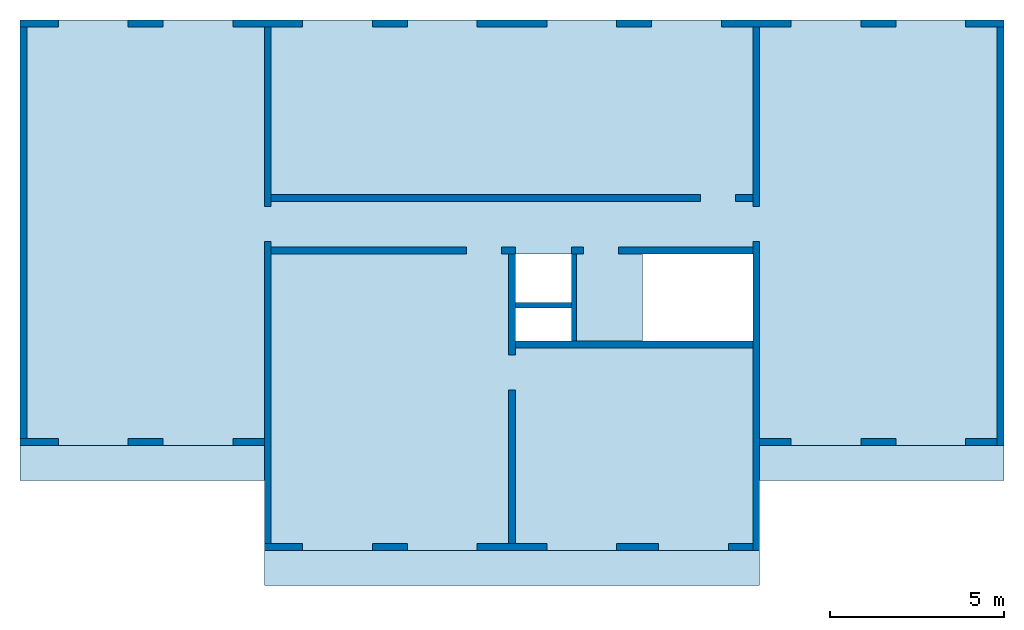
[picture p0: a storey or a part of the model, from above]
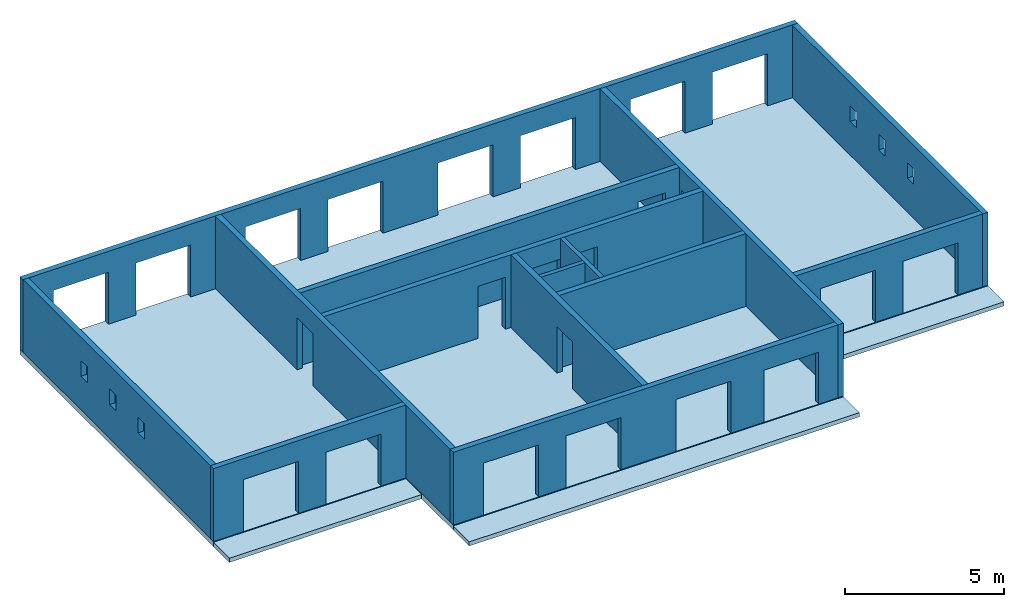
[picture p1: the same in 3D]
Properties of the parts of a building model (IFC2X3)

# File
Description: ViewDefinition [CoordinationView_V2.0, QuantityTakeOffAddOnView]
File name: Numéro de projet
Time: 2019-03-26T11:01:44
Written by: The EXPRESS Data Manager Version 5.02.0100.07 : 28 Aug 2013
Made in: 20180328_1600(x64) - Exporter 19.0.1.1 - Interface utilisateur alternative 19.0.1.1
Comment: STEP Physical File produced by: The EXPRESS Data Manager Version 5.02.0100.07 : 28 Aug 2013 * Module: EDMstepFileFactory/EDMstandAlone * Creation date: Tue Mar 26 11:01:44 2019 * Host: OCULUS-DGC * Database: C:\Users\TECHNI~1\AppData\Local\Temp\{C029B240-C833-49DC-BA55-EF145CA80EA0}\ifc * Database version: 5507 * Database creation date: Tue Mar 26 11:01:41 2019 * Schema: IFC2X3 * Model: DataRepository.ifc * Model creation date: Tue Mar 26 11:01:41 2019 * Header model: DataRepository.ifc_HeaderModel * Header model creation date: Tue Mar 26 11:01:41 2019 * EDMuser: sdai-user * EDMgroup: sdai-group * License ID and type: 5605 : Permanent license. Expiry date: * EDMstepFileFactory options: 020000

# IfcProject, Numéro de projet
LongName: Nom du projet; Phase: Etat du projet

# IfcSite, Default
RefLatitude: 48, 51, 57, 604064; RefLongitude: 2, 19, 58, 799800; RefElevation: 0 m

# IfcBuilding
Pset_BuildingCommon - NumberOfStoreys: 9

# IfcBuildingStorey (9)
Name | LongName | Elevation (m)
Fondations | Fondations | -3.3
R-1 | R-1 | -3
Rez de Chaussée | Rez de Chaussée | 0
R+1 | R+1 | 3
R+2 | R+2 | 6
R+3 | R+3 | 9
R+4 | R+4 | 12
R+5 | R+5 | 15
R+6 | R+6 | 18

# IfcFooting: Semelle filante:Soubassement de soutènement - 300 x 600 x 300 (8)
In: Fondations
PredefinedType: STRIP_FOOTING
Name (Semelle filante:Soubassement de soutènement - 300 x 600 x 300:...)
463532
463540
463560
463574
463588
463598
463612
463626

# IfcMember: Limon à la française:Limon à la française - 50 mm de largeur (60)
Type - PredefinedType: STRINGER
Pset_MemberCommon - LoadBearing: yes; IsExternal: no; Reference: Contremarche 190 mm max marche 250 mm
BaseQuantities - NetSurfaceArea: 35.8411 m2; NetVolume: 0.668562 m3
Name (Escalier assemblé:Escalier:...) | In | Span (m) = Length (m) | Slope (deg) | CrossSectionArea (m2) | OuterSurfaceArea (m2) | GrossSurfaceArea (m2) | GrossVolume (m3)
467169 Stringer 1 | Rez de Chaussée | 0.05 | 0 | 0.899041 | 0.270884 | 2.06897 | 0.044952
467169 Stringer 2 | Rez de Chaussée | 0.05 | 0 | 0.899041 | 0.270884 | 2.06897 | 0.044952
467169 Stringer 3 | Rez de Chaussée | 0.05 | 0 | 0.97861 | 0.290776 | 2.248 | 0.0489305
467169 Stringer 4 | Rez de Chaussée | 0.05 | 0 | 0.97861 | 0.290776 | 2.248 | 0.0489305
467169 Stringer 5 | Rez de Chaussée
467169 Stringer 6 | Rez de Chaussée | 0.4 | 0 | 0.115 | 1.89657 | 2.12657 | 0.046
467169 Stringer 7 | Rez de Chaussée
467169 Stringer 8 | Rez de Chaussée
467169 Stringer 9 | Rez de Chaussée | 0.4 | 0 | 0.01 | 0.216569 | 0.236569 | 0.004
467169 Stringer 10 | Rez de Chaussée
468124 Stringer 1 | R+2 | 0.05 | 0 | 0.899041 | 0.270884 | 2.06897 | 0.044952
468124 Stringer 2 | R+2 | 0.05 | 0 | 0.899041 | 0.270884 | 2.06897 | 0.044952
468124 Stringer 3 | R+2 | 0.05 | 0 | 0.97861 | 0.290776 | 2.248 | 0.0489305
468124 Stringer 4 | R+2 | 0.05 | 0 | 0.97861 | 0.290776 | 2.248 | 0.0489305
468124 Stringer 5 | R+2
468124 Stringer 6 | R+2 | 0.4 | 0 | 0.115 | 1.89657 | 2.12657 | 0.046
468124 Stringer 7 | R+2
468124 Stringer 8 | R+2
468124 Stringer 9 | R+2 | 0.4 | 0 | 0.01 | 0.216569 | 0.236569 | 0.004
468124 Stringer 10 | R+2
468213 Stringer 1 | R+3 | 0.05 | 0 | 0.899041 | 0.270884 | 2.06897 | 0.044952
468213 Stringer 2 | R+3 | 0.05 | 0 | 0.899041 | 0.270884 | 2.06897 | 0.044952
468213 Stringer 3 | R+3 | 0.05 | 0 | 0.97861 | 0.290776 | 2.248 | 0.0489305
468213 Stringer 4 | R+3 | 0.05 | 0 | 0.97861 | 0.290776 | 2.248 | 0.0489305
468213 Stringer 5 | R+3
468213 Stringer 6 | R+3 | 0.4 | 0 | 0.115 | 1.89657 | 2.12657 | 0.046
468213 Stringer 7 | R+3
468213 Stringer 8 | R+3
468213 Stringer 9 | R+3 | 0.4 | 0 | 0.01 | 0.216569 | 0.236569 | 0.004
468213 Stringer 10 | R+3
468302 Stringer 1 | R+4 | 0.05 | 0 | 0.899041 | 0.270884 | 2.06897 | 0.044952
468302 Stringer 2 | R+4 | 0.05 | 0 | 0.899041 | 0.270884 | 2.06897 | 0.044952
468302 Stringer 3 | R+4 | 0.05 | 0 | 0.97861 | 0.290776 | 2.248 | 0.0489305
468302 Stringer 4 | R+4 | 0.05 | 0 | 0.97861 | 0.290776 | 2.248 | 0.0489305
468302 Stringer 5 | R+4
468302 Stringer 6 | R+4 | 0.4 | 0 | 0.115 | 1.89657 | 2.12657 | 0.046
468302 Stringer 7 | R+4
468302 Stringer 8 | R+4
468302 Stringer 9 | R+4 | 0.4 | 0 | 0.01 | 0.216569 | 0.236569 | 0.004
468302 Stringer 10 | R+4
468480 Stringer 1 | R-1 | 0.05 | 0 | 0.899041 | 0.270884 | 2.06897 | 0.044952
468480 Stringer 2 | R-1 | 0.05 | 0 | 0.899041 | 0.270884 | 2.06897 | 0.044952
468480 Stringer 3 | R-1 | 0.05 | 0 | 0.97861 | 0.290776 | 2.248 | 0.0489305
468480 Stringer 4 | R-1 | 0.05 | 0 | 0.97861 | 0.290776 | 2.248 | 0.0489305
468480 Stringer 5 | R-1
468480 Stringer 6 | R-1 | 0.4 | 0 | 0.115 | 1.89657 | 2.12657 | 0.046
468480 Stringer 7 | R-1
468480 Stringer 8 | R-1
468480 Stringer 9 | R-1 | 0.4 | 0 | 0.01 | 0.216569 | 0.236569 | 0.004
468480 Stringer 10 | R-1
468584 Stringer 1 | R+1 | 0.05 | 0 | 0.899041 | 0.270884 | 2.06897 | 0.044952
468584 Stringer 2 | R+1 | 0.05 | 0 | 0.899041 | 0.270884 | 2.06897 | 0.044952
468584 Stringer 3 | R+1 | 0.05 | 0 | 0.97861 | 0.290776 | 2.248 | 0.0489305
468584 Stringer 4 | R+1 | 0.05 | 0 | 0.97861 | 0.290776 | 2.248 | 0.0489305
468584 Stringer 5 | R+1
468584 Stringer 6 | R+1 | 0.4 | 0 | 0.115 | 1.89657 | 2.12657 | 0.046
468584 Stringer 7 | R+1
468584 Stringer 8 | R+1
468584 Stringer 9 | R+1 | 0.4 | 0 | 0.01 | 0.216569 | 0.236569 | 0.004
468584 Stringer 10 | R+1

# IfcOpeningElement: Opening (196)
Name | In | Depth (m) | Height (m) | Width (m)
Sol:Dalle pleine 200 mm:449392:2 | R+1 | 0.2 | 1.4 | 1.6 | Nomenclature des sols - Structure: yes; Coefficient d'absorbance: 0.7; Décalage par rapport au niveau: 0.2 m; Elévation au niveau du noyau inférieur: 3 m; Elévation au niveau du noyau supérieur: 3.2 m; Elévation en haut: 3.2 m; Elévation à la base: 3 m; Epaisseur du porteur: 0.2 m; Epaisseur par défaut: 0.2 m; Etude de l'élévation en haut: 3.2 m; Etude de l'élévation à la base: 3 m; Famille: Sol: Dalle pleine 200 mm; Famille et type: Sol: Dalle pleine 200 mm; Matériau structurel: Béton - Coulé sur place - Béton20; Niveau: Niveau: R+1; Phase de création: Nouvelle construction; Périmètre: 109.22 m; Rugosité: 3; Surface: 374.98 m2; Type: Sol: Dalle pleine 200 mm; Volume: 74.996 m3
Sol:Dalle pleine 200 mm:449392:3 | R+1 | 0.2 | 0.95 | 1.6 | Nomenclature des sols - Structure: yes; Coefficient d'absorbance: 0.7; Décalage par rapport au niveau: 0.2 m; Elévation au niveau du noyau inférieur: 3 m; Elévation au niveau du noyau supérieur: 3.2 m; Elévation en haut: 3.2 m; Elévation à la base: 3 m; Epaisseur du porteur: 0.2 m; Epaisseur par défaut: 0.2 m; Etude de l'élévation en haut: 3.2 m; Etude de l'élévation à la base: 3 m; Famille: Sol: Dalle pleine 200 mm; Famille et type: Sol: Dalle pleine 200 mm; Matériau structurel: Béton - Coulé sur place - Béton20; Niveau: Niveau: R+1; Phase de création: Nouvelle construction; Périmètre: 109.22 m; Rugosité: 3; Surface: 374.98 m2; Type: Sol: Dalle pleine 200 mm; Volume: 74.996 m3
Sol:Dalle pleine 200 mm:449392:4 | R+1 | 0.2 | 3.16 | 2.5 | Nomenclature des sols - Structure: yes; Coefficient d'absorbance: 0.7; Décalage par rapport au niveau: 0.2 m; Elévation au niveau du noyau inférieur: 3 m; Elévation au niveau du noyau supérieur: 3.2 m; Elévation en haut: 3.2 m; Elévation à la base: 3 m; Epaisseur du porteur: 0.2 m; Epaisseur par défaut: 0.2 m; Etude de l'élévation en haut: 3.2 m; Etude de l'élévation à la base: 3 m; Famille: Sol: Dalle pleine 200 mm; Famille et type: Sol: Dalle pleine 200 mm; Matériau structurel: Béton - Coulé sur place - Béton20; Niveau: Niveau: R+1; Phase de création: Nouvelle construction; Périmètre: 109.22 m; Rugosité: 3; Surface: 374.98 m2; Type: Sol: Dalle pleine 200 mm; Volume: 74.996 m3
Sol:Dalle pleine 200 mm:456217:2 | R+2 | 0.2 | 1.4 | 1.6 | Nomenclature des sols - Structure: yes; Coefficient d'absorbance: 0.7; Décalage par rapport au niveau: 0.2 m; Elévation au niveau du noyau inférieur: 6 m; Elévation au niveau du noyau supérieur: 6.2 m; Elévation en haut: 6.2 m; Elévation à la base: 6 m; Epaisseur du porteur: 0.2 m; Epaisseur par défaut: 0.2 m; Etude de l'élévation en haut: 6.2 m; Etude de l'élévation à la base: 6 m; Famille: Sol: Dalle pleine 200 mm; Famille et type: Sol: Dalle pleine 200 mm; Matériau structurel: Béton - Coulé sur place - Béton20; Niveau: Niveau: R+2; Phase de création: Nouvelle construction; Périmètre: 109.22 m; Rugosité: 3; Surface: 374.98 m2; Type: Sol: Dalle pleine 200 mm; Volume: 74.996 m3
Sol:Dalle pleine 200 mm:456217:3 | R+2 | 0.2 | 0.95 | 1.6 | Nomenclature des sols - Structure: yes; Coefficient d'absorbance: 0.7; Décalage par rapport au niveau: 0.2 m; Elévation au niveau du noyau inférieur: 6 m; Elévation au niveau du noyau supérieur: 6.2 m; Elévation en haut: 6.2 m; Elévation à la base: 6 m; Epaisseur du porteur: 0.2 m; Epaisseur par défaut: 0.2 m; Etude de l'élévation en haut: 6.2 m; Etude de l'élévation à la base: 6 m; Famille: Sol: Dalle pleine 200 mm; Famille et type: Sol: Dalle pleine 200 mm; Matériau structurel: Béton - Coulé sur place - Béton20; Niveau: Niveau: R+2; Phase de création: Nouvelle construction; Périmètre: 109.22 m; Rugosité: 3; Surface: 374.98 m2; Type: Sol: Dalle pleine 200 mm; Volume: 74.996 m3
Sol:Dalle pleine 200 mm:456217:4 | R+2 | 0.2 | 3.16 | 2.5 | Nomenclature des sols - Structure: yes; Coefficient d'absorbance: 0.7; Décalage par rapport au niveau: 0.2 m; Elévation au niveau du noyau inférieur: 6 m; Elévation au niveau du noyau supérieur: 6.2 m; Elévation en haut: 6.2 m; Elévation à la base: 6 m; Epaisseur du porteur: 0.2 m; Epaisseur par défaut: 0.2 m; Etude de l'élévation en haut: 6.2 m; Etude de l'élévation à la base: 6 m; Famille: Sol: Dalle pleine 200 mm; Famille et type: Sol: Dalle pleine 200 mm; Matériau structurel: Béton - Coulé sur place - Béton20; Niveau: Niveau: R+2; Phase de création: Nouvelle construction; Périmètre: 109.22 m; Rugosité: 3; Surface: 374.98 m2; Type: Sol: Dalle pleine 200 mm; Volume: 74.996 m3
Sol:Dalle pleine 200 mm:456393:2 | R+3 | 0.2 | 1.4 | 1.6 | Nomenclature des sols - Structure: yes; Coefficient d'absorbance: 0.7; Décalage par rapport au niveau: 0.2 m; Elévation au niveau du noyau inférieur: 9 m; Elévation au niveau du noyau supérieur: 9.2 m; Elévation en haut: 9.2 m; Elévation à la base: 9 m; Epaisseur du porteur: 0.2 m; Epaisseur par défaut: 0.2 m; Etude de l'élévation en haut: 9.2 m; Etude de l'élévation à la base: 9 m; Famille: Sol: Dalle pleine 200 mm; Famille et type: Sol: Dalle pleine 200 mm; Matériau structurel: Béton - Coulé sur place - Béton20; Niveau: Niveau: R+3; Phase de création: Nouvelle construction; Périmètre: 109.22 m; Rugosité: 3; Surface: 374.98 m2; Type: Sol: Dalle pleine 200 mm; Volume: 74.996 m3
Sol:Dalle pleine 200 mm:456393:3 | R+3 | 0.2 | 0.95 | 1.6 | Nomenclature des sols - Structure: yes; Coefficient d'absorbance: 0.7; Décalage par rapport au niveau: 0.2 m; Elévation au niveau du noyau inférieur: 9 m; Elévation au niveau du noyau supérieur: 9.2 m; Elévation en haut: 9.2 m; Elévation à la base: 9 m; Epaisseur du porteur: 0.2 m; Epaisseur par défaut: 0.2 m; Etude de l'élévation en haut: 9.2 m; Etude de l'élévation à la base: 9 m; Famille: Sol: Dalle pleine 200 mm; Famille et type: Sol: Dalle pleine 200 mm; Matériau structurel: Béton - Coulé sur place - Béton20; Niveau: Niveau: R+3; Phase de création: Nouvelle construction; Périmètre: 109.22 m; Rugosité: 3; Surface: 374.98 m2; Type: Sol: Dalle pleine 200 mm; Volume: 74.996 m3
Sol:Dalle pleine 200 mm:456393:4 | R+3 | 0.2 | 3.16 | 2.5 | Nomenclature des sols - Structure: yes; Coefficient d'absorbance: 0.7; Décalage par rapport au niveau: 0.2 m; Elévation au niveau du noyau inférieur: 9 m; Elévation au niveau du noyau supérieur: 9.2 m; Elévation en haut: 9.2 m; Elévation à la base: 9 m; Epaisseur du porteur: 0.2 m; Epaisseur par défaut: 0.2 m; Etude de l'élévation en haut: 9.2 m; Etude de l'élévation à la base: 9 m; Famille: Sol: Dalle pleine 200 mm; Famille et type: Sol: Dalle pleine 200 mm; Matériau structurel: Béton - Coulé sur place - Béton20; Niveau: Niveau: R+3; Phase de création: Nouvelle construction; Périmètre: 109.22 m; Rugosité: 3; Surface: 374.98 m2; Type: Sol: Dalle pleine 200 mm; Volume: 74.996 m3
Sol:Dalle pleine 200 mm:456569:2 | R+4 | 0.2 | 1.4 | 1.6 | Nomenclature des sols - Structure: yes; Coefficient d'absorbance: 0.7; Décalage par rapport au niveau: 0.2 m; Elévation au niveau du noyau inférieur: 12 m; Elévation au niveau du noyau supérieur: 12.2 m; Elévation en haut: 12.2 m; Elévation à la base: 12 m; Epaisseur du porteur: 0.2 m; Epaisseur par défaut: 0.2 m; Etude de l'élévation en haut: 12.2 m; Etude de l'élévation à la base: 12 m; Famille: Sol: Dalle pleine 200 mm; Famille et type: Sol: Dalle pleine 200 mm; Matériau structurel: Béton - Coulé sur place - Béton20; Niveau: Niveau: R+4; Phase de création: Nouvelle construction; Périmètre: 109.22 m; Rugosité: 3; Surface: 374.98 m2; Type: Sol: Dalle pleine 200 mm; Volume: 74.996 m3
Sol:Dalle pleine 200 mm:456569:3 | R+4 | 0.2 | 0.95 | 1.6 | Nomenclature des sols - Structure: yes; Coefficient d'absorbance: 0.7; Décalage par rapport au niveau: 0.2 m; Elévation au niveau du noyau inférieur: 12 m; Elévation au niveau du noyau supérieur: 12.2 m; Elévation en haut: 12.2 m; Elévation à la base: 12 m; Epaisseur du porteur: 0.2 m; Epaisseur par défaut: 0.2 m; Etude de l'élévation en haut: 12.2 m; Etude de l'élévation à la base: 12 m; Famille: Sol: Dalle pleine 200 mm; Famille et type: Sol: Dalle pleine 200 mm; Matériau structurel: Béton - Coulé sur place - Béton20; Niveau: Niveau: R+4; Phase de création: Nouvelle construction; Périmètre: 109.22 m; Rugosité: 3; Surface: 374.98 m2; Type: Sol: Dalle pleine 200 mm; Volume: 74.996 m3
Sol:Dalle pleine 200 mm:456569:4 | R+4 | 0.2 | 3.16 | 2.5 | Nomenclature des sols - Structure: yes; Coefficient d'absorbance: 0.7; Décalage par rapport au niveau: 0.2 m; Elévation au niveau du noyau inférieur: 12 m; Elévation au niveau du noyau supérieur: 12.2 m; Elévation en haut: 12.2 m; Elévation à la base: 12 m; Epaisseur du porteur: 0.2 m; Epaisseur par défaut: 0.2 m; Etude de l'élévation en haut: 12.2 m; Etude de l'élévation à la base: 12 m; Famille: Sol: Dalle pleine 200 mm; Famille et type: Sol: Dalle pleine 200 mm; Matériau structurel: Béton - Coulé sur place - Béton20; Niveau: Niveau: R+4; Phase de création: Nouvelle construction; Périmètre: 109.22 m; Rugosité: 3; Surface: 374.98 m2; Type: Sol: Dalle pleine 200 mm; Volume: 74.996 m3
Sol:Dalle pleine 200 mm:456745:2 | R+5 | 0.2 | 1.4 | 1.6 | Nomenclature des sols - Structure: yes; Coefficient d'absorbance: 0.7; Décalage par rapport au niveau: 0.2 m; Elévation au niveau du noyau inférieur: 15 m; Elévation au niveau du noyau supérieur: 15.2 m; Elévation en haut: 15.2 m; Elévation à la base: 15 m; Epaisseur du porteur: 0.2 m; Epaisseur par défaut: 0.2 m; Etude de l'élévation en haut: 15.2 m; Etude de l'élévation à la base: 15 m; Famille: Sol: Dalle pleine 200 mm; Famille et type: Sol: Dalle pleine 200 mm; Matériau structurel: Béton - Coulé sur place - Béton20; Niveau: Niveau: R+5; Phase de création: Nouvelle construction; Périmètre: 109.22 m; Rugosité: 3; Surface: 374.98 m2; Type: Sol: Dalle pleine 200 mm; Volume: 74.996 m3
Sol:Dalle pleine 200 mm:456745:3 | R+5 | 0.2 | 0.95 | 1.6 | Nomenclature des sols - Structure: yes; Coefficient d'absorbance: 0.7; Décalage par rapport au niveau: 0.2 m; Elévation au niveau du noyau inférieur: 15 m; Elévation au niveau du noyau supérieur: 15.2 m; Elévation en haut: 15.2 m; Elévation à la base: 15 m; Epaisseur du porteur: 0.2 m; Epaisseur par défaut: 0.2 m; Etude de l'élévation en haut: 15.2 m; Etude de l'élévation à la base: 15 m; Famille: Sol: Dalle pleine 200 mm; Famille et type: Sol: Dalle pleine 200 mm; Matériau structurel: Béton - Coulé sur place - Béton20; Niveau: Niveau: R+5; Phase de création: Nouvelle construction; Périmètre: 109.22 m; Rugosité: 3; Surface: 374.98 m2; Type: Sol: Dalle pleine 200 mm; Volume: 74.996 m3
Sol:Dalle pleine 200 mm:456745:4 | R+5 | 0.2 | 3.16 | 2.5 | Nomenclature des sols - Structure: yes; Coefficient d'absorbance: 0.7; Décalage par rapport au niveau: 0.2 m; Elévation au niveau du noyau inférieur: 15 m; Elévation au niveau du noyau supérieur: 15.2 m; Elévation en haut: 15.2 m; Elévation à la base: 15 m; Epaisseur du porteur: 0.2 m; Epaisseur par défaut: 0.2 m; Etude de l'élévation en haut: 15.2 m; Etude de l'élévation à la base: 15 m; Famille: Sol: Dalle pleine 200 mm; Famille et type: Sol: Dalle pleine 200 mm; Matériau structurel: Béton - Coulé sur place - Béton20; Niveau: Niveau: R+5; Phase de création: Nouvelle construction; Périmètre: 109.22 m; Rugosité: 3; Surface: 374.98 m2; Type: Sol: Dalle pleine 200 mm; Volume: 74.996 m3
Sol:Dalle pleine 200 mm:457097:2 | Rez de Chaussée | 0.2 | 1.4 | 1.6 | Nomenclature des sols - Structure: yes; Coefficient d'absorbance: 0.7; Décalage par rapport au niveau: 0.2 m; Elévation au niveau du noyau inférieur: 0 m; Elévation au niveau du noyau supérieur: 0.2 m; Elévation en haut: 0.2 m; Elévation à la base: 0 m; Epaisseur du porteur: 0.2 m; Epaisseur par défaut: 0.2 m; Etude de l'élévation en haut: 0.2 m; Etude de l'élévation à la base: 0 m; Famille: Sol: Dalle pleine 200 mm; Famille et type: Sol: Dalle pleine 200 mm; Matériau structurel: Béton - Coulé sur place - Béton20; Niveau: Niveau: Rez de Chaussée; Phase de création: Nouvelle construction; Périmètre: 109.22 m; Rugosité: 3; Surface: 374.98 m2; Type: Sol: Dalle pleine 200 mm; Volume: 74.996 m3
Sol:Dalle pleine 200 mm:457097:3 | Rez de Chaussée | 0.2 | 0.95 | 1.6 | Nomenclature des sols - Structure: yes; Coefficient d'absorbance: 0.7; Décalage par rapport au niveau: 0.2 m; Elévation au niveau du noyau inférieur: 0 m; Elévation au niveau du noyau supérieur: 0.2 m; Elévation en haut: 0.2 m; Elévation à la base: 0 m; Epaisseur du porteur: 0.2 m; Epaisseur par défaut: 0.2 m; Etude de l'élévation en haut: 0.2 m; Etude de l'élévation à la base: 0 m; Famille: Sol: Dalle pleine 200 mm; Famille et type: Sol: Dalle pleine 200 mm; Matériau structurel: Béton - Coulé sur place - Béton20; Niveau: Niveau: Rez de Chaussée; Phase de création: Nouvelle construction; Périmètre: 109.22 m; Rugosité: 3; Surface: 374.98 m2; Type: Sol: Dalle pleine 200 mm; Volume: 74.996 m3
Sol:Dalle pleine 200 mm:457097:4 | Rez de Chaussée | 0.2 | 3.16 | 2.5 | Nomenclature des sols - Structure: yes; Coefficient d'absorbance: 0.7; Décalage par rapport au niveau: 0.2 m; Elévation au niveau du noyau inférieur: 0 m; Elévation au niveau du noyau supérieur: 0.2 m; Elévation en haut: 0.2 m; Elévation à la base: 0 m; Epaisseur du porteur: 0.2 m; Epaisseur par défaut: 0.2 m; Etude de l'élévation en haut: 0.2 m; Etude de l'élévation à la base: 0 m; Famille: Sol: Dalle pleine 200 mm; Famille et type: Sol: Dalle pleine 200 mm; Matériau structurel: Béton - Coulé sur place - Béton20; Niveau: Niveau: Rez de Chaussée; Phase de création: Nouvelle construction; Périmètre: 109.22 m; Rugosité: 3; Surface: 374.98 m2; Type: Sol: Dalle pleine 200 mm; Volume: 74.996 m3
Mur de base:Générique - 200 mm:461218 | R-1 | 3.048 | 1 | 2
8 x Mur de base:Générique - 200 mm:445545 | R+1 | 3.048 | 2 | 2
3 x Mur de base:Générique - 200 mm:445684 | R+1 | 3.048 | 0.6 | 0.4
2 x Mur de base:Générique - 200 mm:445779 | R+1 | 3.048 | 2 | 2
Mur de base:Générique - 200 mm:445868 | R+1 | 3.048 | 2 | 1
4 x Mur de base:Générique - 200 mm:446047 | R+1 | 3.048 | 2 | 2
Mur de base:Générique - 200 mm:461216 | R-1 | 3.048 | 1 | 2
Mur de base:Générique - 200 mm:446108 | R+1 | 3.048 | 1 | 2
2 x Mur de base:Générique - 200 mm:446185 | R+1 | 3.048 | 2 | 2
3 x Mur de base:Générique - 200 mm:446292 | R+1 | 3.048 | 0.4 | 0.6
Mur de base:Générique - 200 mm:446712 | R+1 | 3.048 | 1 | 2
Mur de base:Générique - 200 mm:446815 | R+1 | 3.048 | 2 | 1
Mur de base:Générique - 200 mm:446815 | R+1 | 3.048 | 1 | 2
Mur de base:Générique - 200 mm:446815 | R+1 | 3.048 | 1.6 | 2
Mur de base:Générique - 200 mm:446951 | R+1 | 3.048 | 2 | 1
8 x Mur de base:Générique - 200 mm:456187 |  | 3.048 | 2 | 2
3 x Mur de base:Générique - 200 mm:456189 | R+2 | 3.048 | 0.6 | 0.4
Mur de base:Générique - 200 mm:461214 | R-1 | 3.048 | 1.6 | 2
2 x Mur de base:Générique - 200 mm:456191 | R+2 | 3.048 | 2 | 2
Mur de base:Générique - 200 mm:456193 | R+2 | 3.048 | 2 | 1
4 x Mur de base:Générique - 200 mm:456195 | R+2 | 3.048 | 2 | 2
Mur de base:Générique - 200 mm:456197 | R+2 | 3.048 | 1 | 2
2 x Mur de base:Générique - 200 mm:456199 | R+2 | 3.048 | 2 | 2
3 x Mur de base:Générique - 200 mm:456201 | R+2 | 3.048 | 0.4 | 0.6
Mur de base:Générique - 200 mm:456203 | R+2 | 3.048 | 1 | 2
Mur de base:Générique - 200 mm:456205 | R+2 | 3.048 | 2 | 1
Mur de base:Générique - 200 mm:456205 | R+2 | 3.048 | 1 | 2
Mur de base:Générique - 200 mm:456205 | R+2 | 3.048 | 1.6 | 2
Mur de base:Générique - 200 mm:456207 | R+2 | 3.048 | 2 | 1
8 x Mur de base:Générique - 200 mm:456363 | R+3 | 3.048 | 2 | 2
Mur de base:Générique - 200 mm:461214 | R-1 | 3.048 | 1 | 2
3 x Mur de base:Générique - 200 mm:456365 | R+3 | 3.048 | 0.6 | 0.4
2 x Mur de base:Générique - 200 mm:456367 | R+3 | 3.048 | 2 | 2
Mur de base:Générique - 200 mm:456369 | R+3 | 3.048 | 2 | 1
4 x Mur de base:Générique - 200 mm:456371 | R+3 | 3.048 | 2 | 2
Mur de base:Générique - 200 mm:456373 | R+3 | 3.048 | 1 | 2
2 x Mur de base:Générique - 200 mm:456375 | R+3 | 3.048 | 2 | 2
3 x Mur de base:Générique - 200 mm:456377 | R+3 | 3.048 | 0.4 | 0.6
Mur de base:Générique - 200 mm:461210 | R-1 | 3.048 | 3 | 2
Mur de base:Générique - 200 mm:456379 | R+3 | 3.048 | 1 | 2
Mur de base:Générique - 200 mm:456381 | R+3 | 3.048 | 2 | 1
Mur de base:Générique - 200 mm:456381 | R+3 | 3.048 | 1 | 2
Mur de base:Générique - 200 mm:456381 | R+3 | 3.048 | 1.6 | 2
Mur de base:Générique - 200 mm:456383 | R+3 | 3.048 | 2 | 1
8 x Mur de base:Générique - 200 mm:456539 | R+4 | 3.048 | 2 | 2
3 x Mur de base:Générique - 200 mm:456541 | R+4 | 3.048 | 0.6 | 0.4
2 x Mur de base:Générique - 200 mm:456543 | R+4 | 3.048 | 2 | 2
Mur de base:Générique - 200 mm:456545 | R+4 | 3.048 | 2 | 1
4 x Mur de base:Générique - 200 mm:456547 | R+4 | 3.048 | 2 | 2
Mur de base:Générique - 200 mm:460163 | Rez de Chaussée | 3.048 | 2 | 2
Mur de base:Générique - 200 mm:456549 | R+4 | 3.048 | 1 | 2
2 x Mur de base:Générique - 200 mm:456551 | R+4 | 3.048 | 2 | 2
3 x Mur de base:Générique - 200 mm:456553 | R+4 | 3.048 | 0.4 | 0.6
Mur de base:Générique - 200 mm:456555 | R+4 | 3.048 | 1 | 2
Mur de base:Générique - 200 mm:456557 | R+4 | 3.048 | 2 | 1
Mur de base:Générique - 200 mm:456557 | R+4 | 3.048 | 1 | 2
Mur de base:Générique - 200 mm:456557 | R+4 | 3.048 | 1.6 | 2
Mur de base:Générique - 200 mm:456559 | R+4 | 3.048 | 2 | 1
8 x Mur de base:Générique - 200 mm:456715 | R+5 | 3.048 | 2 | 2
3 x Mur de base:Générique - 200 mm:456717 | R+5 | 3.048 | 0.6 | 0.4
Mur de base:Générique - 200 mm:457089 | Rez de Chaussée | 3.048 | 2 | 2
2 x Mur de base:Générique - 200 mm:456719 | R+5 | 3.048 | 2 | 2
Mur de base:Générique - 200 mm:456721 | R+5 | 3.048 | 2 | 1
4 x Mur de base:Générique - 200 mm:456723 | R+5 | 3.048 | 2 | 2
Mur de base:Générique - 200 mm:456725 | R+5 | 3.048 | 1 | 2
2 x Mur de base:Générique - 200 mm:456727 | R+5 | 3.048 | 2 | 2
3 x Mur de base:Générique - 200 mm:456729 | R+5 | 3.048 | 0.4 | 0.6
Mur de base:Générique - 200 mm:456731 | R+5 | 3.048 | 1 | 2
Mur de base:Générique - 200 mm:456733 | R+5 | 3.048 | 2 | 1
Mur de base:Générique - 200 mm:456733 | R+5 | 3.048 | 1 | 2
Mur de base:Générique - 200 mm:456733 | R+5 | 3.048 | 1.6 | 2
Mur de base:Générique - 200 mm:456735 | R+5 | 3.048 | 2 | 1
8 x Mur de base:Générique - 200 mm:457067 | Rez de Chaussée | 3.048 | 2 | 2
Mur de base:Générique - 200 mm:457085 | Rez de Chaussée | 3.048 | 2 | 2
3 x Mur de base:Générique - 200 mm:457069 | Rez de Chaussée | 3.048 | 0.6 | 0.4
2 x Mur de base:Générique - 200 mm:457071 | Rez de Chaussée | 3.048 | 2 | 2
Mur de base:Générique - 200 mm:457073 | Rez de Chaussée | 3.048 | 2 | 1
2 x Mur de base:Générique - 200 mm:457075 | Rez de Chaussée | 3.048 | 2 | 2
Mur de base:Générique - 200 mm:457085 | Rez de Chaussée | 3.048 | 1.6 | 2
Mur de base:Générique - 200 mm:457077 | Rez de Chaussée | 3.048 | 1 | 2
2 x Mur de base:Générique - 200 mm:457079 | Rez de Chaussée | 3.048 | 2 | 2
3 x Mur de base:Générique - 200 mm:457081 | Rez de Chaussée | 3.048 | 0.4 | 0.6
Mur de base:Générique - 200 mm:457083 | Rez de Chaussée | 3.048 | 1 | 2
Mur de base:Générique - 200 mm:457085 | Rez de Chaussée | 3.048 | 1 | 2

# IfcRailing: Garde-corps:900mm (12)
Pset_RailingCommon - IsExternal: no; Reference: 900mm; Height: 0.9 m
Name (Garde-corps:900mm:...) | In | Length (m)
467527 | Rez de Chaussée | 5.79573
467531 | Rez de Chaussée | 9.41253
468139 | R+2 | 5.79573
468143 | R+2 | 9.41253
468228 | R+3 | 5.79573
468232 | R+3 | 9.41253
468317 | R+4 | 5.79573
468321 | R+4 | 9.41253
468495 | R-1 | 5.79573
468499 | R-1 | 9.41253
468599 | R+1 | 5.79573
468603 | R+1 | 9.41253

# IfcSlab: Escalier assemblé:Contremarche 190 mm max marche 250 mm:176014 (6)
PredefinedType: LANDING
Pset_SlabCommon - IsExternal: no; PitchAngle: 0 deg; Reference: Palier non-monobloc
BaseQuantities - GrossArea: 3.0475 m2; GrossVolume: 0.152375 m3; Perimeter: 8.32 m; Width: 0.05 m
Name (Escalier assemblé:Escalier:...) | In
467169 Landing 1 | Rez de Chaussée
468124 Landing 1 | R+2
468213 Landing 1 | R+3
468302 Landing 1 | R+4
468480 Landing 1 | R-1
468584 Landing 1 | R+1

# IfcSlab: Sol:Balcon 160 mm (5)
PredefinedType: FLOOR; Material: Béton - Coulé sur place - Béton20 0.16 m
Pset_SlabCommon - LoadBearing: yes; IsExternal: no; Reference: Balcon 160 mm
Nomenclature des sols - Structure: yes; Coefficient d'absorbance: 0.7; Décalage par rapport au niveau: 0.16 m; Epaisseur par défaut: 0.16 m; Famille: Sol: Balcon 160 mm; Famille et type: Sol: Balcon 160 mm; Matériau structurel: Béton - Coulé sur place - Béton20; Phase de création: Nouvelle construction; Périmètre: 62.4 m; Rugosité: 3; Surface: 28.2014 m2; Type: Sol: Balcon 160 mm; Volume: 4.653 m3
Name (Sol:Balcon 160 mm:...) | In | Elévation au niveau du noyau inférieur (m) = Elévation à la base (m) = Etude de l'élévation à la base (m) | Niveau
450322 | R+1 | 3 | Niveau: R+1
456260 | R+2 | 6 | Niveau: R+2
456436 | R+3 | 9 | Niveau: R+3
456612 | R+4 | 12 | Niveau: R+4
456788 | R+5 | 15 | Niveau: R+5

# IfcSlab: Sol:Dalle pleine 200 mm (9)
PredefinedType: FLOOR; Material: Béton - Coulé sur place - Béton20 0.2 m
Pset_SlabCommon - LoadBearing: yes; Reference: Dalle pleine 200 mm; IsExternal: no
Nomenclature des sols - Coefficient d'absorbance: 0.7; Epaisseur par défaut: 0.2 m; Famille: Sol: Dalle pleine 200 mm; Famille et type: Sol: Dalle pleine 200 mm; Matériau structurel: Béton - Coulé sur place - Béton20; Phase de création: Nouvelle construction; Rugosité: 3; Structure: yes; Type: Sol: Dalle pleine 200 mm
Name (Sol:Dalle pleine 200 mm:...) | In | Décalage par rapport au niveau (m) | Elévation au niveau du noyau inférieur (m) = Elévation à la base (m) = Etude de l'élévation à la base (m) | Elévation au niveau du noyau supérieur (m) = Elévation en haut (m) = Etude de l'élévation en haut (m) | Epaisseur du porteur (m) | Niveau | Périmètre (m) | Surface (m2) | Volume (m3) | GrossArea (m2) | Perimeter (m)
449392 | R+1 | 0.2 | 3 | 3.2 | 0.2 | Niveau: R+1 | 109.22 | 374.98 | 74.996 | 386.64 | 86.8
456217 | R+2 | 0.2 | 6 | 6.2 | 0.2 | Niveau: R+2 | 109.22 | 374.98 | 74.996 | 386.64 | 86.8
456393 | R+3 | 0.2 | 9 | 9.2 | 0.2 | Niveau: R+3 | 109.22 | 374.98 | 74.996 | 386.64 | 86.8
456569 | R+4 | 0.2 | 12 | 12.2 | 0.2 | Niveau: R+4 | 109.22 | 374.98 | 74.996 | 386.64 | 86.8
456745 | R+5 | 0.2 | 15 | 15.2 | 0.2 | Niveau: R+5 | 109.22 | 374.98 | 74.996 | 386.64 | 86.8
457097 | Rez de Chaussée | 0.2 | 0 | 0.2 | 0.2 | Niveau: Rez de Chaussée | 109.22 | 374.98 | 74.996 | 386.64 | 86.8
461226 | R-1 | 0.2 | -3 | -2.8 | 0.2 | Niveau: R-1 | 86.8 | 386.64 | 77.328 | 386.64 | 86.8 | Pset_SlabCommon - PitchAngle: 0 deg; BaseQuantities - GrossVolume: 77.328 m3; Width: 0.2 m
463931 | Fondations | 0 |  |  |  | Niveau: Fondations | 46 | 60.6712 | 12.1342 | 60.6712 | 46.4475 | Pset_SlabCommon - PitchAngle: 0 deg; BaseQuantities - GrossVolume: 12.27 m3; Width: 0.202237 m
464137 | R+6 | 0.2 | 18 | 18.2 | 0.2 | Niveau: R+6 | 86.8 | 386.64 | 77.328 | 386.64 | 86.8 | Pset_SlabCommon - PitchAngle: 0 deg; BaseQuantities - GrossVolume: 77.328 m3; Width: 0.2 m

# IfcStair: Escalier assemblé:Contremarche 190 mm max marche 250 mm:176014 (6)
Pset_StairCommon - IsExternal: no; Reference: Contremarche 190 mm max marche 250 mm; NumberOfRiser: 16; NumberOfTreads: 14; RiserHeight: 0.188235 m; TreadLength: 0.25 m
Name (Escalier assemblé:Escalier:...) | In
467169 | Rez de Chaussée
468124 | R+2
468213 | R+3
468302 | R+4
468480 | R-1
468584 | R+1

# IfcStairFlight: Escalier assemblé:Contremarche 190 mm max marche 250 mm:176014 (12)
NumberOfRiser: 8; NumberOfTreads: 7; RiserHeight: 0.61757 m; TreadLength: 0.82021 m
Pset_StairFlightCommon - Reference: Marche 50 mm Contremarche 13 mm; NumberOfRiser: 16; NumberOfTreads: 14; RiserHeight: 0.188235 m; TreadLength: 0.25 m; TreadLengthAtOffset: 0.25 m; NosingLength: 0 m; WalkingLineOffset: 0.5 m; WaistThickness: 1 m
Name (Escalier assemblé:Escalier:...) | In
467169 Run 1 | Rez de Chaussée
467169 Run 2 | Rez de Chaussée
468124 Run 1 | R+2
468124 Run 2 | R+2
468213 Run 1 | R+3
468213 Run 2 | R+3
468302 Run 1 | R+4
468302 Run 2 | R+4
468480 Run 1 | R-1
468480 Run 2 | R-1
468584 Run 1 | R+1
468584 Run 2 | R+1

# IfcWallStandardCase: Mur de base:Générique - 150 mm (14)
Type - PredefinedType: STANDARD; Material: Blocs béton manufacturés 0.15 m
BaseQuantities - Width: 0.15 m
Pset_WallCommon - LoadBearing: yes; ExtendToStructure: no; IsExternal: yes; Reference: Générique - 150 mm; ThermalTransmittance: 8.66667 kg/K/s3
Nomenclature de mur - Décalage supérieur: 0 m; Coefficient d'absorbance: 0.7; Coefficient de transfert de chaleur (U): 8.66667; Famille: Mur de base: Générique - 150 mm; Famille et type: Mur de base: Générique - 150 mm; Largeur: 0.15 m; Masse thermique: 226800; Matériau structurel: Blocs béton manufacturés; Phase de création: Nouvelle construction; Rugosité: 3; Résistance thermique (R): 0.115385; Type: Mur de base: Générique - 150 mm
Name (Mur de base:Générique - 150 mm:...) | In | Height (m) = Hauteur non contrainte (m) | Length (m) | GrossFootprintArea (m2) | GrossSideArea (m2) = Surface (m2) | GrossVolume (m3) = Volume (m3) | Contrainte inférieure | Contrainte supérieure | Décalage inférieur (m) | Longueur (m)
447200 | R+1 | 2.8 | 2.5 | 0.375 | 7 | 1.05 | Niveau: R+1 | Niveau: R+2 | 0.2 | 2.7
447342 | R+1 | 3 | 1.6 | 0.24 | 4.8 | 0.72 | Niveau: R+1 | Niveau: R+2 | 0 | 1.775
456211 | R+2 | 2.8 | 2.5 | 0.375 | 7 | 1.05 | Niveau: R+2 | Niveau: R+3 | 0.2 | 2.7
456213 | R+2 | 3 | 1.6 | 0.24 | 4.8 | 0.72 | Niveau: R+2 | Niveau: R+3 | 0 | 1.775
456387 | R+3 | 2.8 | 2.5 | 0.375 | 7 | 1.05 | Niveau: R+3 | Niveau: R+4 | 0.2 | 2.7
456389 | R+3 | 3 | 1.6 | 0.24 | 4.8 | 0.72 | Niveau: R+3 | Niveau: R+4 | 0 | 1.775
456563 | R+4 | 2.8 | 2.5 | 0.375 | 7 | 1.05 | Niveau: R+4 | Niveau: R+5 | 0.2 | 2.7
456565 | R+4 | 3 | 1.6 | 0.24 | 4.8 | 0.72 | Niveau: R+4 | Niveau: R+5 | 0 | 1.775
456739 | R+5 | 2.8 | 2.5 | 0.375 | 7 | 1.05 | Niveau: R+5 | Niveau: R+6 | 0.2 | 2.7
456741 | R+5 | 3 | 1.6 | 0.24 | 4.8 | 0.72 | Niveau: R+5 | Niveau: R+6 | 0 | 1.775
457091 | Rez de Chaussée | 2.8 | 2.5 | 0.375 | 7 | 1.05 | Niveau: Rez de Chaussée | Niveau: R+1 | 0.2 | 2.7
457093 | Rez de Chaussée | 3 | 1.6 | 0.24 | 4.8 | 0.72 | Niveau: Rez de Chaussée | Niveau: R+1 | 0 | 1.775
461220 | R-1 | 2.8 | 2.5 | 0.375 | 7 | 1.05 | Niveau: R-1 | Niveau: Rez de Chaussée | 0.2 | 2.7
461222 | R-1 | 2.8 | 1.6 | 0.24 | 4.48 | 0.672 | Niveau: R-1 | Niveau: Rez de Chaussée | 0.2 | 1.775

# IfcWallStandardCase: Mur de base:Générique - 200 mm (92)
Type - PredefinedType: STANDARD; Material: Béton - Coulé sur place - Béton20 0.2 m
BaseQuantities - Width: 0.2 m
Pset_WallCommon - Reference: Générique - 200 mm; LoadBearing: yes; ExtendToStructure: no; IsExternal: yes
Nomenclature de mur - Coefficient d'absorbance: 0.7; Décalage supérieur: 0 m; Famille: Mur de base: Générique - 200 mm; Famille et type: Mur de base: Générique - 200 mm; Largeur: 0.2 m; Matériau structurel: Béton - Coulé sur place - Béton20; Phase de création: Nouvelle construction; Rugosité: 3; Type: Mur de base: Générique - 200 mm
Name (Mur de base:Générique - 200 mm:...) | In | Height (m) = Hauteur non contrainte (m) | Length (m) | GrossFootprintArea (m2) | GrossSideArea (m2) = Surface (m2) | GrossVolume (m3) = Volume (m3) | Contrainte inférieure | Contrainte supérieure | Décalage inférieur (m) | Longueur (m)
445545 | R+1 | 2.8 | 28.2 | 5.64 | 46.96 | 9.392 | Niveau: R+1 | Niveau: R+2 | 0.2 | 28
445684 | R+1 | 2.8 | 12 | 2.4 | 32.88 | 6.576 | Niveau: R+1 | Niveau: R+2 | 0.2 | 12
445779 | R+1 | 2.8 | 6.8 | 1.36 | 11.04 | 2.208 | Niveau: R+1 | Niveau: R+2 | 0.2 | 7
445868 | R+1 | 2.8 | 15 | 3 | 40 | 8 | Niveau: R+1 | Niveau: R+2 | 0.2 | 15
446047 | R+1 | 2.8 | 14 | 2.8 | 23.2 | 4.64 | Niveau: R+1 | Niveau: R+2 | 0.2 | 14
446108 | R+1 | 2.8 | 14.8 | 2.96 | 39.44 | 7.888 | Niveau: R+1 | Niveau: R+2 | 0.2 | 15
446185 | R+1 | 2.8 | 7 | 1.4 | 11.6 | 2.32 | Niveau: R+1 | Niveau: R+2 | 0.2 | 7
446292 | R+1 | 2.8 | 11.8 | 2.36 | 32.32 | 6.464 | Niveau: R+1 | Niveau: R+2 | 0.2 | 12
446712 | R+1 | 2.8 | 13.8 | 2.76 | 36.64 | 7.328 | Niveau: R+1 | Niveau: R+2 | 0.2 | 14
446815 | R+1 | 2.8 | 13.8 | 2.76 | 31.44 | 6.288 | Niveau: R+1 | Niveau: R+2 | 0.2 | 14
446951 | R+1 | 2.8 | 8.3 | 1.66 | 21.44 | 4.288 | Niveau: R+1 | Niveau: R+2 | 0.2 | 8.5
447029 | R+1 | 2.8 | 6.8 | 1.36 | 19.04 | 3.808 | Niveau: R+1 | Niveau: R+2 | 0.2 | 7
456189 | R+2 | 2.8 | 12 | 2.4 | 32.88 | 6.576 | Niveau: R+2 | Niveau: R+3 | 0.2 | 12
456191 | R+2 | 2.8 | 6.8 | 1.36 | 11.04 | 2.208 | Niveau: R+2 | Niveau: R+3 | 0.2 | 7
456193 | R+2 | 2.8 | 15 | 3 | 40 | 8 | Niveau: R+2 | Niveau: R+3 | 0.2 | 15
456195 | R+2 | 2.8 | 14 | 2.8 | 23.2 | 4.64 | Niveau: R+2 | Niveau: R+3 | 0.2 | 14
456197 | R+2 | 2.8 | 14.8 | 2.96 | 39.44 | 7.888 | Niveau: R+2 | Niveau: R+3 | 0.2 | 15
456199 | R+2 | 2.8 | 7 | 1.4 | 11.6 | 2.32 | Niveau: R+2 | Niveau: R+3 | 0.2 | 7
456201 | R+2 | 2.8 | 11.8 | 2.36 | 32.32 | 6.464 | Niveau: R+2 | Niveau: R+3 | 0.2 | 12
456203 | R+2 | 2.8 | 13.8 | 2.76 | 36.64 | 7.328 | Niveau: R+2 | Niveau: R+3 | 0.2 | 14
456205 | R+2 | 2.8 | 13.8 | 2.76 | 31.44 | 6.288 | Niveau: R+2 | Niveau: R+3 | 0.2 | 14
456207 | R+2 | 2.8 | 8.3 | 1.66 | 21.44 | 4.288 | Niveau: R+2 | Niveau: R+3 | 0.2 | 8.5
456209 | R+2 | 2.8 | 6.8 | 1.36 | 19.04 | 3.808 | Niveau: R+2 | Niveau: R+3 | 0.2 | 7
456363 | R+3 | 2.8 | 28.2 | 5.64 | 46.96 | 9.392 | Niveau: R+3 | Niveau: R+4 | 0.2 | 28
456365 | R+3 | 2.8 | 12 | 2.4 | 32.88 | 6.576 | Niveau: R+3 | Niveau: R+4 | 0.2 | 12
456367 | R+3 | 2.8 | 6.8 | 1.36 | 11.04 | 2.208 | Niveau: R+3 | Niveau: R+4 | 0.2 | 7
456369 | R+3 | 2.8 | 15 | 3 | 40 | 8 | Niveau: R+3 | Niveau: R+4 | 0.2 | 15
456371 | R+3 | 2.8 | 14 | 2.8 | 23.2 | 4.64 | Niveau: R+3 | Niveau: R+4 | 0.2 | 14
456373 | R+3 | 2.8 | 14.8 | 2.96 | 39.44 | 7.888 | Niveau: R+3 | Niveau: R+4 | 0.2 | 15
456375 | R+3 | 2.8 | 7 | 1.4 | 11.6 | 2.32 | Niveau: R+3 | Niveau: R+4 | 0.2 | 7
456377 | R+3 | 2.8 | 11.8 | 2.36 | 32.32 | 6.464 | Niveau: R+3 | Niveau: R+4 | 0.2 | 12
456379 | R+3 | 2.8 | 13.8 | 2.76 | 36.64 | 7.328 | Niveau: R+3 | Niveau: R+4 | 0.2 | 14
456381 | R+3 | 2.8 | 13.8 | 2.76 | 31.44 | 6.288 | Niveau: R+3 | Niveau: R+4 | 0.2 | 14
456383 | R+3 | 2.8 | 8.3 | 1.66 | 21.44 | 4.288 | Niveau: R+3 | Niveau: R+4 | 0.2 | 8.5
456385 | R+3 | 2.8 | 6.8 | 1.36 | 19.04 | 3.808 | Niveau: R+3 | Niveau: R+4 | 0.2 | 7
456539 | R+4 | 2.8 | 28.2 | 5.64 | 46.96 | 9.392 | Niveau: R+4 | Niveau: R+5 | 0.2 | 28
456541 | R+4 | 2.8 | 12 | 2.4 | 32.88 | 6.576 | Niveau: R+4 | Niveau: R+5 | 0.2 | 12
456543 | R+4 | 2.8 | 6.8 | 1.36 | 11.04 | 2.208 | Niveau: R+4 | Niveau: R+5 | 0.2 | 7
456545 | R+4 | 2.8 | 15 | 3 | 40 | 8 | Niveau: R+4 | Niveau: R+5 | 0.2 | 15
456547 | R+4 | 2.8 | 14 | 2.8 | 23.2 | 4.64 | Niveau: R+4 | Niveau: R+5 | 0.2 | 14
456549 | R+4 | 2.8 | 14.8 | 2.96 | 39.44 | 7.888 | Niveau: R+4 | Niveau: R+5 | 0.2 | 15
456551 | R+4 | 2.8 | 7 | 1.4 | 11.6 | 2.32 | Niveau: R+4 | Niveau: R+5 | 0.2 | 7
456553 | R+4 | 2.8 | 11.8 | 2.36 | 32.32 | 6.464 | Niveau: R+4 | Niveau: R+5 | 0.2 | 12
456555 | R+4 | 2.8 | 13.8 | 2.76 | 36.64 | 7.328 | Niveau: R+4 | Niveau: R+5 | 0.2 | 14
456557 | R+4 | 2.8 | 13.8 | 2.76 | 31.44 | 6.288 | Niveau: R+4 | Niveau: R+5 | 0.2 | 14
456559 | R+4 | 2.8 | 8.3 | 1.66 | 21.44 | 4.288 | Niveau: R+4 | Niveau: R+5 | 0.2 | 8.5
456561 | R+4 | 2.8 | 6.8 | 1.36 | 19.04 | 3.808 | Niveau: R+4 | Niveau: R+5 | 0.2 | 7
456715 | R+5 | 2.8 | 28.2 | 5.64 | 46.96 | 9.392 | Niveau: R+5 | Niveau: R+6 | 0.2 | 28
456717 | R+5 | 2.8 | 12 | 2.4 | 32.88 | 6.576 | Niveau: R+5 | Niveau: R+6 | 0.2 | 12
456719 | R+5 | 2.8 | 6.8 | 1.36 | 11.04 | 2.208 | Niveau: R+5 | Niveau: R+6 | 0.2 | 7
456721 | R+5 | 2.8 | 15 | 3 | 40 | 8 | Niveau: R+5 | Niveau: R+6 | 0.2 | 15
456723 | R+5 | 2.8 | 14 | 2.8 | 23.2 | 4.64 | Niveau: R+5 | Niveau: R+6 | 0.2 | 14
456725 | R+5 | 2.8 | 14.8 | 2.96 | 39.44 | 7.888 | Niveau: R+5 | Niveau: R+6 | 0.2 | 15
456727 | R+5 | 2.8 | 7 | 1.4 | 11.6 | 2.32 | Niveau: R+5 | Niveau: R+6 | 0.2 | 7
456729 | R+5 | 2.8 | 11.8 | 2.36 | 32.32 | 6.464 | Niveau: R+5 | Niveau: R+6 | 0.2 | 12
456731 | R+5 | 2.8 | 13.8 | 2.76 | 36.64 | 7.328 | Niveau: R+5 | Niveau: R+6 | 0.2 | 14
456733 | R+5 | 2.8 | 13.8 | 2.76 | 31.44 | 6.288 | Niveau: R+5 | Niveau: R+6 | 0.2 | 14
456735 | R+5 | 2.8 | 8.3 | 1.66 | 21.44 | 4.288 | Niveau: R+5 | Niveau: R+6 | 0.2 | 8.5
456737 | R+5 | 2.8 | 6.8 | 1.36 | 19.04 | 3.808 | Niveau: R+5 | Niveau: R+6 | 0.2 | 7
457067 | Rez de Chaussée | 2.8 | 28.2 | 5.64 | 46.96 | 9.392 | Niveau: Rez de Chaussée | Niveau: R+1 | 0.2 | 28
457069 | Rez de Chaussée | 2.8 | 12 | 2.4 | 32.88 | 6.576 | Niveau: Rez de Chaussée | Niveau: R+1 | 0.2 | 12
457071 | Rez de Chaussée | 2.8 | 6.8 | 1.36 | 11.04 | 2.208 | Niveau: Rez de Chaussée | Niveau: R+1 | 0.2 | 7
457073 | Rez de Chaussée | 2.8 | 15 | 3 | 40 | 8 | Niveau: Rez de Chaussée | Niveau: R+1 | 0.2 | 15
457075 | Rez de Chaussée | 2.8 | 14 | 2.8 | 32 | 6.4 | Niveau: Rez de Chaussée | Niveau: R+1 | 0.2 | 14
457077 | Rez de Chaussée | 2.8 | 14.8 | 2.96 | 39.44 | 7.888 | Niveau: Rez de Chaussée | Niveau: R+1 | 0.2 | 15
457079 | Rez de Chaussée | 2.8 | 7 | 1.4 | 11.6 | 2.32 | Niveau: Rez de Chaussée | Niveau: R+1 | 0.2 | 7
457081 | Rez de Chaussée | 2.8 | 11.8 | 2.36 | 32.32 | 6.464 | Niveau: Rez de Chaussée | Niveau: R+1 | 0.2 | 12
457083 | Rez de Chaussée | 2.8 | 13.8 | 2.76 | 36.64 | 7.328 | Niveau: Rez de Chaussée | Niveau: R+1 | 0.2 | 14
457085 | Rez de Chaussée | 2.8 | 13.8 | 2.76 | 29.84 | 5.968 | Niveau: Rez de Chaussée | Niveau: R+1 | 0.2 | 14
457087 | Rez de Chaussée | 2.8 | 8.3 | 1.66 | 23.24 | 4.648 | Niveau: Rez de Chaussée | Niveau: R+1 | 0.2 | 8.5
457089 | Rez de Chaussée | 2.8 | 6.8 | 1.36 | 15.44 | 3.088 | Niveau: Rez de Chaussée | Niveau: R+1 | 0.2 | 7
460163 | Rez de Chaussée | 2.8 | 8.3 | 1.66 | 19.64 | 3.928 | Niveau: Rez de Chaussée | Niveau: R+1 | 0.2 | 8.5
461196 | R-1 | 2.8 | 28.2 | 5.64 | 78.96 | 15.792 | Niveau: R-1 | Niveau: Rez de Chaussée | 0.2 | 28
461198 | R-1 | 2.8 | 12 | 2.4 | 33.6 | 6.72 | Niveau: R-1 | Niveau: Rez de Chaussée | 0.2 | 12
461200 | R-1 | 2.8 | 6.8 | 1.36 | 19.04 | 3.808 | Niveau: R-1 | Niveau: Rez de Chaussée | 0.2 | 7
461202 | R-1 | 2.8 | 3.2 | 0.64 | 8.96 | 1.792 | Niveau: R-1 | Niveau: Rez de Chaussée | 0.2 | 3
461204 | R-1 | 2.8 | 14 | 2.8 | 39.2 | 7.84 | Niveau: R-1 | Niveau: Rez de Chaussée | 0.2 | 14
461206 | R-1 | 2.8 | 3 | 0.6 | 8.4 | 1.68 | Niveau: R-1 | Niveau: Rez de Chaussée | 0.2 | 3
461208 | R-1 | 2.8 | 7 | 1.4 | 19.6 | 3.92 | Niveau: R-1 | Niveau: Rez de Chaussée | 0.2 | 7
461210 | R-1 | 2.8 | 11.8 | 2.36 | 27.64 | 5.528 | Niveau: R-1 | Niveau: Rez de Chaussée | 0.2 | 12
461214 | R-1 | 2.8 | 7.2 | 1.44 | 14.96 | 2.992 | Niveau: R-1 | Niveau: Rez de Chaussée | 0.2 | 7
461216 | R-1 | 2.8 | 8.3 | 1.66 | 21.44 | 4.288 | Niveau: R-1 | Niveau: Rez de Chaussée | 0.2 | 8.5
461218 | R-1 | 2.8 | 6.8 | 1.36 | 17.24 | 3.448 | Niveau: R-1 | Niveau: Rez de Chaussée | 0.2 | 7
462374 | Fondations | 0.3 | 28.2 | 5.64 | 8.46 | 1.692 | Niveau: Fondations | Niveau: R-1 | 0 | 28
462513 | Fondations | 0.3 | 12 | 2.4 | 3.6 | 0.72 | Niveau: Fondations | Niveau: R-1 | 0 | 12
462606 | Fondations | 0.3 | 7 | 1.4 | 2.1 | 0.42 | Niveau: Fondations | Niveau: R-1 | 0 | 7
462695 | Fondations | 0.3 | 3 | 0.6 | 0.9 | 0.18 | Niveau: Fondations | Niveau: R-1 | 0 | 3
462837 | Fondations | 0.3 | 14 | 2.8 | 4.2 | 0.84 | Niveau: Fondations | Niveau: R-1 | 0 | 14
462912 | Fondations | 0.3 | 3 | 0.6 | 0.9 | 0.18 | Niveau: Fondations | Niveau: R-1 | 0 | 3
462969 | Fondations | 0.3 | 7 | 1.4 | 2.1 | 0.42 | Niveau: Fondations | Niveau: R-1 | 0 | 7
463102 | Fondations | 0.3 | 11.8 | 2.36 | 3.54 | 0.708 | Niveau: Fondations | Niveau: R-1 | 0 | 12
466271 | R-1 | 2.8 | 5.3 | 1.06 | 14.84 | 2.968 | Niveau: R-1 | Niveau: Rez de Chaussée | 0.2 | 5.5
